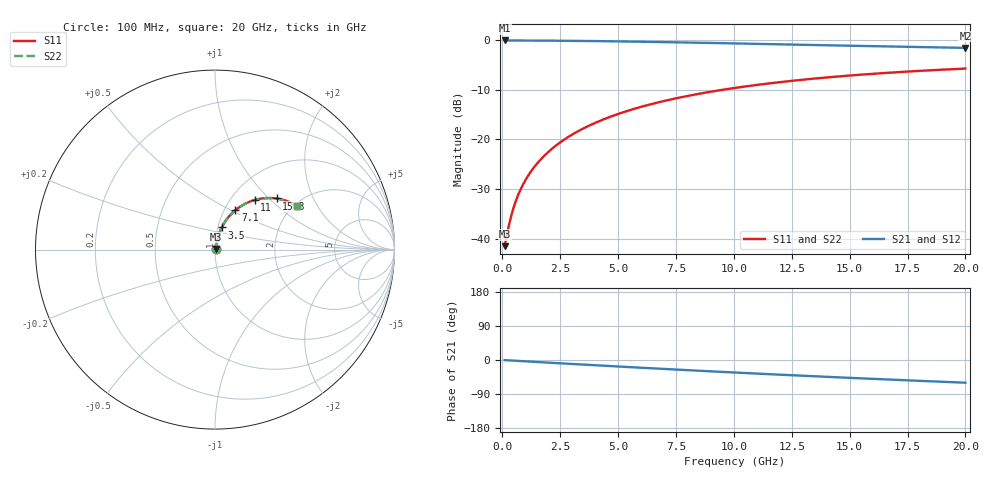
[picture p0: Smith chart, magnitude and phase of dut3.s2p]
! Touchstone file exported from HFSS 2026.1.0
!  File:  C:/ffzhzh/LocalFiles/Ansys_Project_Files/temp_test_BSMRDL_3_1782907222_8056.aedt
!  Generated:  08:01:45 PM Jul  1, 2026
!  Design:  BSMRDL
!  Project:  temp_test_BSMRDL_3_1782907222_8056
! Variables:
!  h_bsmrdl = 4.01um
!  h_ox = 20um
!  h_rdl = 5um
!  h_sub = 80um
!  h_tmrdl = 5um
!  h_tsv = 80um
!  h_via = 3um
!  l_bsmrdl = 958.19um
!  l_sub = 1358.19um
!  l_tmrdl = 200um
!  m_sub = 200um
!  pitch = 32.17um
!  r_tsv = 6um
!  s_tmrdl = 10um
!  w_bsmrdl = 11.31um
!  w_sub = 500um
!  w_tmrdl = 12um
!  x_tsv_center1 = 206um
!  x_tsv_center2 = 1175.5um
!  x_tsv_center3 = 1387.5um
!  x_tsv_center4 = 2357um
!  x_tsv_center5 = 2569um
!  x_tsv_center6 = 3538.5um
# GHz S MA R 50.000000
! Terminal data exported
! Port[1] = BSM_RDL1_1_T1
! Port[2] = BSM_RDL1_1_T2
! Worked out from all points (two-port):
!   200 points, 100 MHz to 20 GHz, reference 50 ohm
!   highest |S21| = -0.06 dB at 100 MHz (marker M1); lowest = -1.6 dB at 20 GHz (marker M2)
!   |S21| within 3 dB of the highest: start of sweep to end of sweep
!   lowest |S11| = -41.5 dB at 100 MHz (marker M3), VSWR 1.02, Z = 50.7 + j0.401 ohm
!   |S11| at or under -10 dB: start of sweep to 9.515 GHz
!   |S22| runs from -41.5 to -5.7 dB; largest |S21 - S12| = 7.9e-15
!   S11 on the Smith chart (normalised r, x): 100 MHz: 1.01, +0.01; 3.5 GHz: 1.04, +0.26; 7.1 GHz: 1.13, +0.53; 11 GHz: 1.28, +0.81; 15.3 GHz: 1.56, +1.11; 20 GHz: 2.06, +1.37
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0.1  0.008428 27.9  0.9926 -0.4  0.9926 -0.4  0.008428 27.9
! Gamma 0 0 0 0
! Port Impedance 50 0 50 0
0.3  0.01412 55.8  0.9922 -1.1  0.9922 -1.1  0.01412 55.8
0.4  0.01752 61.8  0.992 -1.4  0.992 -1.4  0.01752 61.8
0.6  0.02455 68.4  0.9915 -2.1  0.9915 -2.1  0.02455 68.4
0.7  0.02812 70.3  0.9913 -2.5  0.9913 -2.5  0.02812 70.3
0.9  0.03532 72.9  0.9909 -3.2  0.9909 -3.2  0.03532 72.9
1.2  0.0462 74.9  0.9902 -4.2  0.9902 -4.2  0.0462 74.8
1.7  0.06442 75.9  0.9889 -6.0  0.9889 -6.0  0.06442 75.9
2.2  0.0826 75.7  0.9871 -7.7  0.9871 -7.7  0.08261 75.7
2.8  0.1042 74.8  0.9846 -9.8  0.9846 -9.8  0.1042 74.7
3.5  0.1291 73.1  0.981 -12.1  0.981 -12.1  0.1291 73.1
4.2  0.1534 71.2  0.9768 -14.5  0.9768 -14.5  0.1535 71.2
5  0.1805 68.9  0.9713 -17.2  0.9713 -17.2  0.1805 68.9
6.8  0.2382 63.6  0.9569 -23.0  0.9569 -23.0  0.2383 63.5
7.1  0.2474 62.7  0.9543 -24.0  0.9543 -24.0  0.2474 62.6
8.5  0.2884 58.5  0.9416 -28.4  0.9416 -28.4  0.2884 58.4
10.1  0.3316 53.9  0.9262 -33.2  0.9262 -33.2  0.3316 53.7
11  0.3542 51.3  0.9174 -35.9  0.9174 -35.9  0.3543 51.2
13.4  0.4085 44.7  0.8938 -42.7  0.8938 -42.7  0.4087 44.5
15.3  0.4457 39.8  0.8757 -47.9  0.8757 -47.9  0.4458 39.5
16.7  0.4699 36.2  0.863 -51.6  0.863 -51.6  0.4701 35.9
20  0.5171 28.2  0.8361 -59.9  0.8361 -59.9  0.5173 27.9
